VERSION 5.7 ;
  NOWIREEXTENSIONATPIN ON ;
  DIVIDERCHAR "/" ;
  BUSBITCHARS "[]" ;
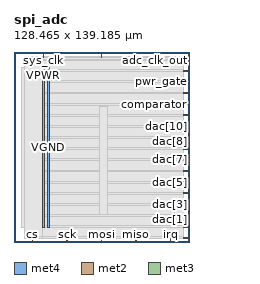
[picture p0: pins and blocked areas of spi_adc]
MACRO spi_adc
  CLASS BLOCK ;
  FOREIGN spi_adc ;
  ORIGIN 0.000 0.000 ;
  SIZE 128.465 BY 139.185 ;
  PIN VGND
    DIRECTION INOUT ;
    USE GROUND ;
    PORT
      LAYER met4 ;
        RECT 24.340 10.640 25.940 128.080 ;
    END
  END VGND
  PIN VPWR
    DIRECTION INOUT ;
    USE POWER ;
    PORT
      LAYER met4 ;
        RECT 21.040 10.640 22.640 128.080 ;
    END
  END VPWR
  PIN adc_clk_out
    DIRECTION OUTPUT ;
    USE SIGNAL ;
    ANTENNADIFFAREA 0.445500 ;
    PORT
      LAYER met2 ;
        RECT 106.810 135.185 107.090 139.185 ;
    END
  END adc_clk_out
  PIN comparator
    DIRECTION INPUT ;
    USE SIGNAL ;
    ANTENNAGATEAREA 0.196500 ;
    PORT
      LAYER met3 ;
        RECT 124.465 100.680 128.465 101.280 ;
    END
  END comparator
  PIN cs
    DIRECTION INPUT ;
    USE SIGNAL ;
    ANTENNAGATEAREA 0.126000 ;
    PORT
      LAYER met2 ;
        RECT 13.430 0.000 13.710 4.000 ;
    END
  END cs
  PIN dac[0]
    DIRECTION OUTPUT ;
    USE SIGNAL ;
    ANTENNADIFFAREA 0.445500 ;
    PORT
      LAYER met3 ;
        RECT 124.465 2.760 128.465 3.360 ;
    END
  END dac[0]
  PIN dac[10]
    DIRECTION OUTPUT ;
    USE SIGNAL ;
    ANTENNADIFFAREA 0.445500 ;
    PORT
      LAYER met3 ;
        RECT 124.465 84.360 128.465 84.960 ;
    END
  END dac[10]
  PIN dac[11]
    DIRECTION OUTPUT ;
    USE SIGNAL ;
    ANTENNADIFFAREA 0.445500 ;
    PORT
      LAYER met3 ;
        RECT 124.465 92.520 128.465 93.120 ;
    END
  END dac[11]
  PIN dac[1]
    DIRECTION OUTPUT ;
    USE SIGNAL ;
    ANTENNADIFFAREA 0.445500 ;
    PORT
      LAYER met3 ;
        RECT 124.465 10.920 128.465 11.520 ;
    END
  END dac[1]
  PIN dac[2]
    DIRECTION OUTPUT ;
    USE SIGNAL ;
    ANTENNADIFFAREA 0.445500 ;
    PORT
      LAYER met3 ;
        RECT 124.465 19.080 128.465 19.680 ;
    END
  END dac[2]
  PIN dac[3]
    DIRECTION OUTPUT ;
    USE SIGNAL ;
    ANTENNADIFFAREA 0.445500 ;
    PORT
      LAYER met3 ;
        RECT 124.465 27.240 128.465 27.840 ;
    END
  END dac[3]
  PIN dac[4]
    DIRECTION OUTPUT ;
    USE SIGNAL ;
    ANTENNADIFFAREA 0.445500 ;
    PORT
      LAYER met3 ;
        RECT 124.465 35.400 128.465 36.000 ;
    END
  END dac[4]
  PIN dac[5]
    DIRECTION OUTPUT ;
    USE SIGNAL ;
    ANTENNADIFFAREA 0.445500 ;
    PORT
      LAYER met3 ;
        RECT 124.465 43.560 128.465 44.160 ;
    END
  END dac[5]
  PIN dac[6]
    DIRECTION OUTPUT ;
    USE SIGNAL ;
    ANTENNADIFFAREA 0.445500 ;
    PORT
      LAYER met3 ;
        RECT 124.465 51.720 128.465 52.320 ;
    END
  END dac[6]
  PIN dac[7]
    DIRECTION OUTPUT ;
    USE SIGNAL ;
    ANTENNADIFFAREA 0.445500 ;
    PORT
      LAYER met3 ;
        RECT 124.465 59.880 128.465 60.480 ;
    END
  END dac[7]
  PIN dac[8]
    DIRECTION OUTPUT ;
    USE SIGNAL ;
    ANTENNADIFFAREA 0.445500 ;
    PORT
      LAYER met3 ;
        RECT 124.465 68.040 128.465 68.640 ;
    END
  END dac[8]
  PIN dac[9]
    DIRECTION OUTPUT ;
    USE SIGNAL ;
    ANTENNADIFFAREA 0.445500 ;
    PORT
      LAYER met3 ;
        RECT 124.465 76.200 128.465 76.800 ;
    END
  END dac[9]
  PIN dac_rst
    DIRECTION OUTPUT ;
    USE SIGNAL ;
    ANTENNADIFFAREA 0.445500 ;
    PORT
      LAYER met3 ;
        RECT 124.465 125.160 128.465 125.760 ;
    END
  END dac_rst
  PIN irq
    DIRECTION OUTPUT ;
    USE SIGNAL ;
    ANTENNADIFFAREA 0.445500 ;
    PORT
      LAYER met2 ;
        RECT 114.630 0.000 114.910 4.000 ;
    END
  END irq
  PIN miso
    DIRECTION OUTPUT ;
    USE SIGNAL ;
    ANTENNADIFFAREA 1.782000 ;
    PORT
      LAYER met2 ;
        RECT 89.330 0.000 89.610 4.000 ;
    END
  END miso
  PIN mosi
    DIRECTION INPUT ;
    USE SIGNAL ;
    ANTENNAGATEAREA 0.196500 ;
    PORT
      LAYER met2 ;
        RECT 64.030 0.000 64.310 4.000 ;
    END
  END mosi
  PIN pwr_gate
    DIRECTION OUTPUT ;
    USE SIGNAL ;
    ANTENNADIFFAREA 0.445500 ;
    PORT
      LAYER met3 ;
        RECT 124.465 117.000 128.465 117.600 ;
    END
  END pwr_gate
  PIN reset_
    DIRECTION INPUT ;
    USE SIGNAL ;
    ANTENNAGATEAREA 0.126000 ;
    PORT
      LAYER met2 ;
        RECT 64.030 135.185 64.310 139.185 ;
    END
  END reset_
  PIN sample_and_hold
    DIRECTION OUTPUT ;
    USE SIGNAL ;
    ANTENNADIFFAREA 0.445500 ;
    PORT
      LAYER met3 ;
        RECT 124.465 108.840 128.465 109.440 ;
    END
  END sample_and_hold
  PIN sck
    DIRECTION INPUT ;
    USE SIGNAL ;
    ANTENNAGATEAREA 0.196500 ;
    PORT
      LAYER met2 ;
        RECT 38.730 0.000 39.010 4.000 ;
    END
  END sck
  PIN sys_clk
    DIRECTION INPUT ;
    USE SIGNAL ;
    ANTENNAGATEAREA 0.852000 ;
    PORT
      LAYER met2 ;
        RECT 21.250 135.185 21.530 139.185 ;
    END
  END sys_clk
  PIN vref_sel
    DIRECTION OUTPUT ;
    USE SIGNAL ;
    ANTENNADIFFAREA 0.445500 ;
    PORT
      LAYER met3 ;
        RECT 124.465 133.320 128.465 133.920 ;
    END
  END vref_sel
  OBS
      LAYER nwell ;
        RECT 5.330 10.795 123.010 128.030 ;
      LAYER li1 ;
        RECT 5.520 10.795 122.820 127.925 ;
      LAYER met1 ;
        RECT 5.520 10.640 122.820 128.080 ;
      LAYER met2 ;
        RECT 7.920 134.905 20.970 135.730 ;
        RECT 21.810 134.905 63.750 135.730 ;
        RECT 64.590 134.905 106.530 135.730 ;
        RECT 107.370 134.905 121.350 135.730 ;
        RECT 7.920 4.280 121.350 134.905 ;
        RECT 7.920 2.875 13.150 4.280 ;
        RECT 13.990 2.875 38.450 4.280 ;
        RECT 39.290 2.875 63.750 4.280 ;
        RECT 64.590 2.875 89.050 4.280 ;
        RECT 89.890 2.875 114.350 4.280 ;
        RECT 115.190 2.875 121.350 4.280 ;
      LAYER met3 ;
        RECT 21.050 132.920 124.065 133.785 ;
        RECT 21.050 126.160 124.465 132.920 ;
        RECT 21.050 124.760 124.065 126.160 ;
        RECT 21.050 118.000 124.465 124.760 ;
        RECT 21.050 116.600 124.065 118.000 ;
        RECT 21.050 109.840 124.465 116.600 ;
        RECT 21.050 108.440 124.065 109.840 ;
        RECT 21.050 101.680 124.465 108.440 ;
        RECT 21.050 100.280 124.065 101.680 ;
        RECT 21.050 93.520 124.465 100.280 ;
        RECT 21.050 92.120 124.065 93.520 ;
        RECT 21.050 85.360 124.465 92.120 ;
        RECT 21.050 83.960 124.065 85.360 ;
        RECT 21.050 77.200 124.465 83.960 ;
        RECT 21.050 75.800 124.065 77.200 ;
        RECT 21.050 69.040 124.465 75.800 ;
        RECT 21.050 67.640 124.065 69.040 ;
        RECT 21.050 60.880 124.465 67.640 ;
        RECT 21.050 59.480 124.065 60.880 ;
        RECT 21.050 52.720 124.465 59.480 ;
        RECT 21.050 51.320 124.065 52.720 ;
        RECT 21.050 44.560 124.465 51.320 ;
        RECT 21.050 43.160 124.065 44.560 ;
        RECT 21.050 36.400 124.465 43.160 ;
        RECT 21.050 35.000 124.065 36.400 ;
        RECT 21.050 28.240 124.465 35.000 ;
        RECT 21.050 26.840 124.065 28.240 ;
        RECT 21.050 20.080 124.465 26.840 ;
        RECT 21.050 18.680 124.065 20.080 ;
        RECT 21.050 11.920 124.465 18.680 ;
        RECT 21.050 10.520 124.065 11.920 ;
        RECT 21.050 3.760 124.465 10.520 ;
        RECT 21.050 2.895 124.065 3.760 ;
      LAYER met4 ;
        RECT 62.855 19.895 68.705 99.105 ;
  END
END spi_adc
END LIBRARY

